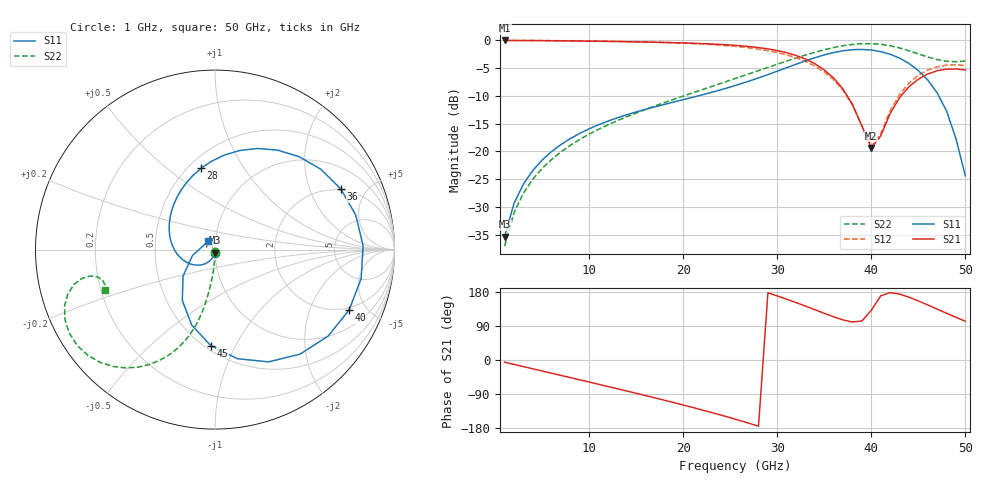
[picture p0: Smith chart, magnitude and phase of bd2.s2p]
! Impedora 0.10.0 via model, case bd2 (fullwave/cases.json), 2026-11-19
! Backdrilled via in the low-loss board: as bl6, with 0.25 mm of barrel left below the stripline: with its pads and traces, ports at the far end of each trace, after the 3D port calibration.
! Ports: 1 = upper end, 2 = lower end, 50 ohm.
! Compared with the edge 3D mesh.
# Hz S RI R 50
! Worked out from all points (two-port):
!   50 points, 1 GHz to 50 GHz, reference 50 ohm
!   highest |S21| = 0.00 dB at 1 GHz (marker M1); lowest = -19.4 dB at 40 GHz (marker M2)
!   |S21| within 3 dB of the highest: start of sweep to 32.45 GHz
!   lowest |S11| = -35.4 dB at 1 GHz (marker M3), VSWR 1.03, Z = 49.8 - j1.69 ohm
!   |S11| at or under -10 dB: start of sweep to 21.57 GHz; 47.17 GHz to end of sweep
!   |S22| runs from -37.1 to -0.6 dB; largest |S21 - S12| = 1.1
!   S11 on the Smith chart (normalised r, x): 1 GHz: 1.00, -0.03; 28 GHz: 0.58, +0.66; 36 GHz: 1.94, +3.32; 40 GHz: 1.86, -3.80; 45 GHz: 0.53, -0.80; 50 GHz: 0.92, +0.08
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1e9  -0.0018 -0.0169  0.9947 -0.1012  0.9987 -0.0495  -0.000127 -0.014
2e9  -0.00713 -0.0332  0.9789 -0.2013  0.9947 -0.0989  -0.000511 -0.028
4e9  -0.0276 -0.0614  0.9165 -0.3937  0.9786 -0.1969  -0.00207 -0.0561
7e9  -0.0776 -0.0853  0.7524 -0.6473  0.9347 -0.3399  -0.00643 -0.0988
1e10  -0.1389 -0.0793  0.5187 -0.838  0.8671 -0.4754  -0.0133 -0.1425
1.4e10  -0.2128 -0.0221  0.137 -0.9641  0.7399 -0.6383  -0.0263 -0.2038
1.8e10  -0.2528 0.0805  -0.268 -0.9205  0.5697 -0.7713  -0.0448 -0.2719
2.2e10  -0.2423 0.2137  -0.6243 -0.6984  0.3559 -0.8582  -0.0735 -0.3523
2.6e10  -0.1611 0.3702  -0.8404 -0.3133  0.1028 -0.8705  -0.1251 -0.4512
2.8e10  -0.0776 0.4529  -0.8587 -0.0797  -0.0314 -0.8345  -0.1677 -0.5079
3.1e10  0.1356 0.5517  -0.7302 0.2598  -0.2179 -0.7078  -0.2679 -0.5943
3.4e10  0.4694 0.5176  -0.418 0.4526  -0.3285 -0.4864  -0.4283 -0.6548
3.6e10  0.7007 0.3381  -0.1853 0.4179  -0.3138 -0.3093  -0.5668 -0.6515
3.8e10  0.8251 0.0221  -0.0469 0.2599  -0.2058 -0.1609  -0.7079 -0.5895
4e10  0.7476 -0.3362  -0.0708 0.081  -0.028 -0.1065  -0.8116 -0.4663
4.1e10  0.6296 -0.4825  -0.136 0.0254  0.0638 -0.1292  -0.836 -0.3904
4.2e10  0.4734 -0.5827  -0.2193 0.00808  0.1406 -0.1845  -0.8383 -0.3144
4.3e10  0.2978 -0.6255  -0.3032 0.0324  0.1904 -0.2646  -0.8196 -0.2463
4.5e10  -0.0242 -0.5346  -0.409 0.1832  0.1852 -0.4484  -0.74 -0.1598
4.7e10  -0.1821 -0.2832  -0.3719 0.3819  0.0598 -0.5761  -0.6547 -0.152
4.8e10  -0.1779 -0.1475  -0.3023 0.4606  -0.0242 -0.5992  -0.6266 -0.1705
5e10  -0.0394 0.0452  -0.1153 0.5294  -0.181 -0.5661  -0.6124 -0.2244
